One B-rep face of a CAD part: STEP entity #105.
In plain terms, the planar face has unit normal (0, -1, 0).
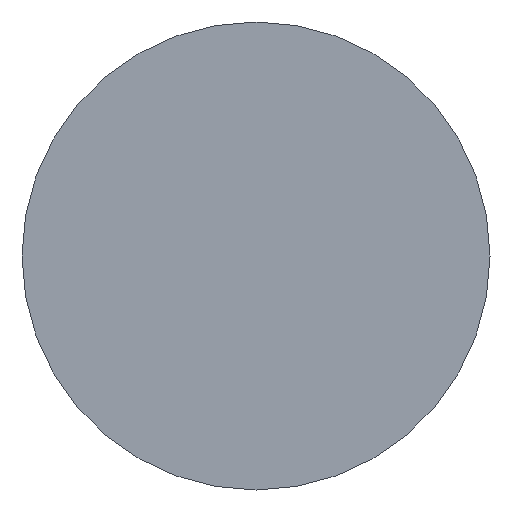
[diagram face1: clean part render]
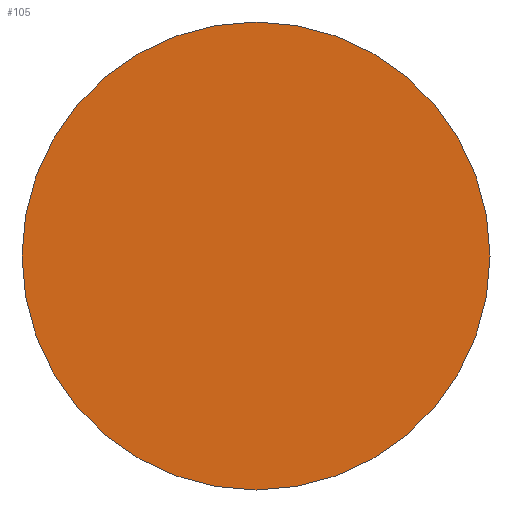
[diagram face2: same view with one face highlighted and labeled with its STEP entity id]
Its self-contained STEP definition (entity closure, numbers rounded to 3 decimals):
#22 = VERTEX_POINT('',#23);
#23 = CARTESIAN_POINT('',(3.15,18.,0.));
#32 = CYLINDRICAL_SURFACE('',#33,3.15);
#33 = AXIS2_PLACEMENT_3D('',#34,#35,#36);
#34 = CARTESIAN_POINT('',(0.,18.,0.));
#35 = DIRECTION('',(0.,-1.,-0.));
#36 = DIRECTION('',(1.,0.,0.));
#79 = EDGE_CURVE('',#22,#22,#80,.T.);
#80 = SURFACE_CURVE('',#81,(#86,#93),.PCURVE_S1.);
#81 = CIRCLE('',#82,3.15);
#82 = AXIS2_PLACEMENT_3D('',#83,#84,#85);
#83 = CARTESIAN_POINT('',(0.,18.,0.));
#84 = DIRECTION('',(-0.,1.,0.));
#85 = DIRECTION('',(1.,0.,0.));
#86 = PCURVE('',#32,#87);
#87 = DEFINITIONAL_REPRESENTATION('',(#88),#92);
#88 = LINE('',#89,#90);
#89 = CARTESIAN_POINT('',(-0.,0.));
#90 = VECTOR('',#91,1.);
#91 = DIRECTION('',(-1.,0.));
#92 = ( GEOMETRIC_REPRESENTATION_CONTEXT(2) 
PARAMETRIC_REPRESENTATION_CONTEXT() REPRESENTATION_CONTEXT('2D SPACE',''
  ) );
#93 = PCURVE('',#94,#99);
#94 = PLANE('',#95);
#95 = AXIS2_PLACEMENT_3D('',#96,#97,#98);
#96 = CARTESIAN_POINT('',(0.,18.,0.));
#97 = DIRECTION('',(0.,1.,0.));
#98 = DIRECTION('',(0.,-0.,1.));
#99 = DEFINITIONAL_REPRESENTATION('',(#100),#104);
#100 = CIRCLE('',#101,3.15);
#101 = AXIS2_PLACEMENT_2D('',#102,#103);
#102 = CARTESIAN_POINT('',(0.,0.));
#103 = DIRECTION('',(0.,1.));
#104 = ( GEOMETRIC_REPRESENTATION_CONTEXT(2) 
PARAMETRIC_REPRESENTATION_CONTEXT() REPRESENTATION_CONTEXT('2D SPACE',''
  ) );
#105 = ADVANCED_FACE('',(#106),#94,.F.);
#106 = FACE_BOUND('',#107,.F.);
#107 = EDGE_LOOP('',(#108));
#108 = ORIENTED_EDGE('',*,*,#79,.T.);
